VERSION 5.8 ;
BUSBITCHARS "[]" ;
DIVIDERCHAR "/" ;
UNITS
    DATABASE MICRONS 1000 ;
END UNITS

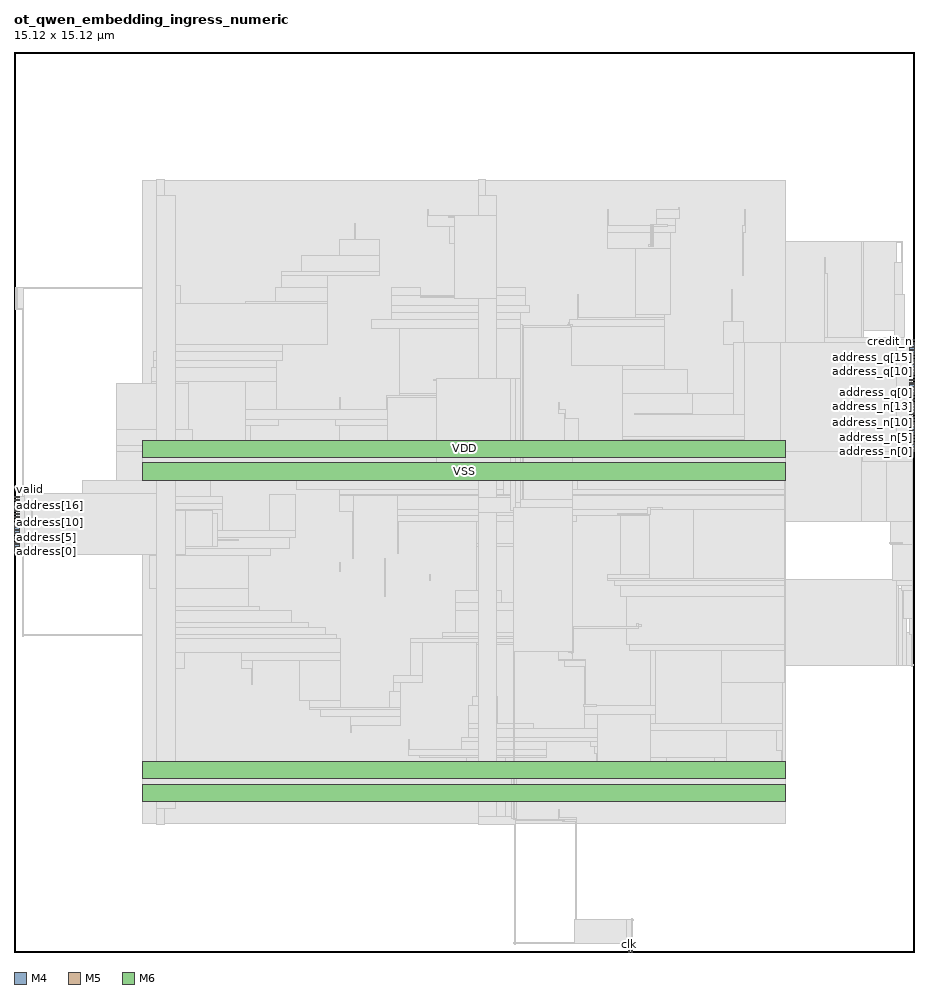
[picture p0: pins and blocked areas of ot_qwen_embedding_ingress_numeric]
MACRO ot_qwen_embedding_ingress_numeric
  FOREIGN ot_qwen_embedding_ingress_numeric 0 0 ;
  CLASS BLOCK ;
  SIZE 15.12 BY 15.12 ;
  PIN address[0]
    DIRECTION INPUT ;
    USE SIGNAL ;
    PORT
      LAYER M4 ;
        RECT  0 6.72 0.084 6.744 ;
    END
  END address[0]
  PIN address[10]
    DIRECTION INPUT ;
    USE SIGNAL ;
    PORT
      LAYER M4 ;
        RECT  0 7.2 0.084 7.224 ;
    END
  END address[10]
  PIN address[11]
    DIRECTION INPUT ;
    USE SIGNAL ;
    PORT
      LAYER M4 ;
        RECT  0 7.248 0.084 7.272 ;
    END
  END address[11]
  PIN address[12]
    DIRECTION INPUT ;
    USE SIGNAL ;
    PORT
      LAYER M4 ;
        RECT  0 7.296 0.084 7.32 ;
    END
  END address[12]
  PIN address[13]
    DIRECTION INPUT ;
    USE SIGNAL ;
    PORT
      LAYER M4 ;
        RECT  0 7.344 0.084 7.368 ;
    END
  END address[13]
  PIN address[14]
    DIRECTION INPUT ;
    USE SIGNAL ;
    PORT
      LAYER M4 ;
        RECT  0 7.392 0.084 7.416 ;
    END
  END address[14]
  PIN address[15]
    DIRECTION INPUT ;
    USE SIGNAL ;
    PORT
      LAYER M4 ;
        RECT  0 7.44 0.084 7.464 ;
    END
  END address[15]
  PIN address[16]
    DIRECTION INPUT ;
    USE SIGNAL ;
    PORT
      LAYER M4 ;
        RECT  0 7.488 0.084 7.512 ;
    END
  END address[16]
  PIN address[17]
    DIRECTION INPUT ;
    USE SIGNAL ;
    PORT
      LAYER M4 ;
        RECT  0 7.536 0.084 7.56 ;
    END
  END address[17]
  PIN address[1]
    DIRECTION INPUT ;
    USE SIGNAL ;
    PORT
      LAYER M4 ;
        RECT  0 6.768 0.084 6.792 ;
    END
  END address[1]
  PIN address[2]
    DIRECTION INPUT ;
    USE SIGNAL ;
    PORT
      LAYER M4 ;
        RECT  0 6.816 0.084 6.84 ;
    END
  END address[2]
  PIN address[3]
    DIRECTION INPUT ;
    USE SIGNAL ;
    PORT
      LAYER M4 ;
        RECT  0 6.864 0.084 6.888 ;
    END
  END address[3]
  PIN address[4]
    DIRECTION INPUT ;
    USE SIGNAL ;
    PORT
      LAYER M4 ;
        RECT  0 6.912 0.084 6.936 ;
    END
  END address[4]
  PIN address[5]
    DIRECTION INPUT ;
    USE SIGNAL ;
    PORT
      LAYER M4 ;
        RECT  0 6.96 0.084 6.984 ;
    END
  END address[5]
  PIN address[6]
    DIRECTION INPUT ;
    USE SIGNAL ;
    PORT
      LAYER M4 ;
        RECT  0 7.008 0.084 7.032 ;
    END
  END address[6]
  PIN address[7]
    DIRECTION INPUT ;
    USE SIGNAL ;
    PORT
      LAYER M4 ;
        RECT  0 7.056 0.084 7.08 ;
    END
  END address[7]
  PIN address[8]
    DIRECTION INPUT ;
    USE SIGNAL ;
    PORT
      LAYER M4 ;
        RECT  0 7.104 0.084 7.128 ;
    END
  END address[8]
  PIN address[9]
    DIRECTION INPUT ;
    USE SIGNAL ;
    PORT
      LAYER M4 ;
        RECT  0 7.152 0.084 7.176 ;
    END
  END address[9]
  PIN address_n[0]
    DIRECTION OUTPUT ;
    USE SIGNAL ;
    PORT
      LAYER M4 ;
        RECT  15.036 8.4 15.12 8.424 ;
    END
  END address_n[0]
  PIN address_n[10]
    DIRECTION OUTPUT ;
    USE SIGNAL ;
    PORT
      LAYER M4 ;
        RECT  15.036 8.88 15.12 8.904 ;
    END
  END address_n[10]
  PIN address_n[11]
    DIRECTION OUTPUT ;
    USE SIGNAL ;
    PORT
      LAYER M4 ;
        RECT  15.036 8.928 15.12 8.952 ;
    END
  END address_n[11]
  PIN address_n[12]
    DIRECTION OUTPUT ;
    USE SIGNAL ;
    PORT
      LAYER M4 ;
        RECT  15.036 8.976 15.12 9 ;
    END
  END address_n[12]
  PIN address_n[13]
    DIRECTION OUTPUT ;
    USE SIGNAL ;
    PORT
      LAYER M4 ;
        RECT  15.036 9.024 15.12 9.048 ;
    END
  END address_n[13]
  PIN address_n[14]
    DIRECTION OUTPUT ;
    USE SIGNAL ;
    PORT
      LAYER M4 ;
        RECT  15.036 9.072 15.12 9.096 ;
    END
  END address_n[14]
  PIN address_n[15]
    DIRECTION OUTPUT ;
    USE SIGNAL ;
    PORT
      LAYER M4 ;
        RECT  15.036 9.12 15.12 9.144 ;
    END
  END address_n[15]
  PIN address_n[16]
    DIRECTION OUTPUT ;
    USE SIGNAL ;
    PORT
      LAYER M4 ;
        RECT  15.036 9.168 15.12 9.192 ;
    END
  END address_n[16]
  PIN address_n[17]
    DIRECTION OUTPUT ;
    USE SIGNAL ;
    PORT
      LAYER M4 ;
        RECT  15.036 9.216 15.12 9.24 ;
    END
  END address_n[17]
  PIN address_n[1]
    DIRECTION OUTPUT ;
    USE SIGNAL ;
    PORT
      LAYER M4 ;
        RECT  15.036 8.448 15.12 8.472 ;
    END
  END address_n[1]
  PIN address_n[2]
    DIRECTION OUTPUT ;
    USE SIGNAL ;
    PORT
      LAYER M4 ;
        RECT  15.036 8.496 15.12 8.52 ;
    END
  END address_n[2]
  PIN address_n[3]
    DIRECTION OUTPUT ;
    USE SIGNAL ;
    PORT
      LAYER M4 ;
        RECT  15.036 8.544 15.12 8.568 ;
    END
  END address_n[3]
  PIN address_n[4]
    DIRECTION OUTPUT ;
    USE SIGNAL ;
    PORT
      LAYER M4 ;
        RECT  15.036 8.592 15.12 8.616 ;
    END
  END address_n[4]
  PIN address_n[5]
    DIRECTION OUTPUT ;
    USE SIGNAL ;
    PORT
      LAYER M4 ;
        RECT  15.036 8.64 15.12 8.664 ;
    END
  END address_n[5]
  PIN address_n[6]
    DIRECTION OUTPUT ;
    USE SIGNAL ;
    PORT
      LAYER M4 ;
        RECT  15.036 8.688 15.12 8.712 ;
    END
  END address_n[6]
  PIN address_n[7]
    DIRECTION OUTPUT ;
    USE SIGNAL ;
    PORT
      LAYER M4 ;
        RECT  15.036 8.736 15.12 8.76 ;
    END
  END address_n[7]
  PIN address_n[8]
    DIRECTION OUTPUT ;
    USE SIGNAL ;
    PORT
      LAYER M4 ;
        RECT  15.036 8.784 15.12 8.808 ;
    END
  END address_n[8]
  PIN address_n[9]
    DIRECTION OUTPUT ;
    USE SIGNAL ;
    PORT
      LAYER M4 ;
        RECT  15.036 8.832 15.12 8.856 ;
    END
  END address_n[9]
  PIN address_q[0]
    DIRECTION OUTPUT ;
    USE SIGNAL ;
    PORT
      LAYER M4 ;
        RECT  15.036 9.264 15.12 9.288 ;
    END
  END address_q[0]
  PIN address_q[10]
    DIRECTION OUTPUT ;
    USE SIGNAL ;
    PORT
      LAYER M4 ;
        RECT  15.036 9.744 15.12 9.768 ;
    END
  END address_q[10]
  PIN address_q[11]
    DIRECTION OUTPUT ;
    USE SIGNAL ;
    PORT
      LAYER M4 ;
        RECT  15.036 9.792 15.12 9.816 ;
    END
  END address_q[11]
  PIN address_q[12]
    DIRECTION OUTPUT ;
    USE SIGNAL ;
    PORT
      LAYER M4 ;
        RECT  15.036 9.84 15.12 9.864 ;
    END
  END address_q[12]
  PIN address_q[13]
    DIRECTION OUTPUT ;
    USE SIGNAL ;
    PORT
      LAYER M4 ;
        RECT  15.036 9.888 15.12 9.912 ;
    END
  END address_q[13]
  PIN address_q[14]
    DIRECTION OUTPUT ;
    USE SIGNAL ;
    PORT
      LAYER M4 ;
        RECT  15.036 9.936 15.12 9.96 ;
    END
  END address_q[14]
  PIN address_q[15]
    DIRECTION OUTPUT ;
    USE SIGNAL ;
    PORT
      LAYER M4 ;
        RECT  15.036 9.984 15.12 10.008 ;
    END
  END address_q[15]
  PIN address_q[16]
    DIRECTION OUTPUT ;
    USE SIGNAL ;
    PORT
      LAYER M4 ;
        RECT  15.036 10.032 15.12 10.056 ;
    END
  END address_q[16]
  PIN address_q[17]
    DIRECTION OUTPUT ;
    USE SIGNAL ;
    PORT
      LAYER M4 ;
        RECT  15.036 10.08 15.12 10.104 ;
    END
  END address_q[17]
  PIN address_q[1]
    DIRECTION OUTPUT ;
    USE SIGNAL ;
    PORT
      LAYER M4 ;
        RECT  15.036 9.312 15.12 9.336 ;
    END
  END address_q[1]
  PIN address_q[2]
    DIRECTION OUTPUT ;
    USE SIGNAL ;
    PORT
      LAYER M4 ;
        RECT  15.036 9.36 15.12 9.384 ;
    END
  END address_q[2]
  PIN address_q[3]
    DIRECTION OUTPUT ;
    USE SIGNAL ;
    PORT
      LAYER M4 ;
        RECT  15.036 9.408 15.12 9.432 ;
    END
  END address_q[3]
  PIN address_q[4]
    DIRECTION OUTPUT ;
    USE SIGNAL ;
    PORT
      LAYER M4 ;
        RECT  15.036 9.456 15.12 9.48 ;
    END
  END address_q[4]
  PIN address_q[5]
    DIRECTION OUTPUT ;
    USE SIGNAL ;
    PORT
      LAYER M4 ;
        RECT  15.036 9.504 15.12 9.528 ;
    END
  END address_q[5]
  PIN address_q[6]
    DIRECTION OUTPUT ;
    USE SIGNAL ;
    PORT
      LAYER M4 ;
        RECT  15.036 9.552 15.12 9.576 ;
    END
  END address_q[6]
  PIN address_q[7]
    DIRECTION OUTPUT ;
    USE SIGNAL ;
    PORT
      LAYER M4 ;
        RECT  15.036 9.6 15.12 9.624 ;
    END
  END address_q[7]
  PIN address_q[8]
    DIRECTION OUTPUT ;
    USE SIGNAL ;
    PORT
      LAYER M4 ;
        RECT  15.036 9.648 15.12 9.672 ;
    END
  END address_q[8]
  PIN address_q[9]
    DIRECTION OUTPUT ;
    USE SIGNAL ;
    PORT
      LAYER M4 ;
        RECT  15.036 9.696 15.12 9.72 ;
    END
  END address_q[9]
  PIN clk
    DIRECTION INPUT ;
    USE SIGNAL ;
    PORT
      LAYER M5 ;
        RECT  10.32 0 10.344 0.084 ;
    END
  END clk
  PIN credit
    DIRECTION INPUT ;
    USE SIGNAL ;
    PORT
      LAYER M4 ;
        RECT  0 7.584 0.084 7.608 ;
    END
  END credit
  PIN credit_n
    DIRECTION OUTPUT ;
    USE SIGNAL ;
    PORT
      LAYER M4 ;
        RECT  15.036 10.128 15.12 10.152 ;
    END
  END credit_n
  PIN credit_q
    DIRECTION OUTPUT ;
    USE SIGNAL ;
    PORT
      LAYER M4 ;
        RECT  15.036 10.176 15.12 10.2 ;
    END
  END credit_q
  PIN rst_n
    DIRECTION INPUT ;
    USE SIGNAL ;
    PORT
      LAYER M5 ;
        RECT  10.368 0 10.392 0.084 ;
    END
  END rst_n
  PIN valid
    DIRECTION INPUT ;
    USE SIGNAL ;
    PORT
      LAYER M4 ;
        RECT  0 7.632 0.084 7.656 ;
    END
  END valid
  PIN valid_n
    DIRECTION OUTPUT ;
    USE SIGNAL ;
    PORT
      LAYER M4 ;
        RECT  15.036 10.224 15.12 10.248 ;
    END
  END valid_n
  PIN valid_q
    DIRECTION OUTPUT ;
    USE SIGNAL ;
    PORT
      LAYER M4 ;
        RECT  15.036 10.272 15.12 10.296 ;
    END
  END valid_q
  PIN VDD
    DIRECTION INOUT ;
    USE POWER ;
    PORT
      LAYER M6 ;
        RECT  2.16 8.313 12.96 8.601 ;
        RECT  2.16 2.913 12.96 3.201 ;
    END
  END VDD
  PIN VSS
    DIRECTION INOUT ;
    USE GROUND ;
    PORT
      LAYER M6 ;
        RECT  2.16 7.929 12.96 8.217 ;
        RECT  2.16 2.529 12.96 2.817 ;
    END
  END VSS
  OBS
    LAYER RVTN ;
     RECT  2.16 2.16 12.96 2.295 ;
     RECT  2.16 2.565 12.96 2.835 ;
     RECT  2.16 3.105 12.96 3.375 ;
     RECT  2.16 3.645 12.96 3.915 ;
     RECT  2.16 4.185 12.96 4.455 ;
     RECT  2.16 4.725 12.96 4.995 ;
     RECT  2.16 5.265 12.96 5.535 ;
     RECT  2.16 5.805 12.96 6.075 ;
     RECT  2.16 6.345 12.96 6.615 ;
     RECT  2.16 6.885 12.96 7.155 ;
     RECT  2.16 7.425 12.96 7.695 ;
     RECT  2.16 7.965 12.96 8.235 ;
     RECT  2.16 8.505 12.96 8.775 ;
     RECT  2.16 9.045 12.96 9.315 ;
     RECT  2.16 9.585 12.96 9.855 ;
     RECT  2.16 10.125 12.96 10.395 ;
     RECT  2.16 10.665 12.96 10.935 ;
     RECT  2.16 11.205 12.96 11.475 ;
     RECT  2.16 11.745 12.96 12.015 ;
     RECT  2.16 12.285 12.96 12.555 ;
     RECT  2.16 12.825 12.96 12.96 ;
    LAYER RVTP ;
     RECT  2.16 2.295 12.96 2.565 ;
     RECT  2.16 2.835 12.96 3.105 ;
     RECT  2.16 3.375 12.96 3.645 ;
     RECT  2.16 3.915 12.96 4.185 ;
     RECT  2.16 4.455 12.96 4.725 ;
     RECT  2.16 4.995 12.96 5.265 ;
     RECT  2.16 5.535 12.96 5.805 ;
     RECT  2.16 6.075 12.96 6.345 ;
     RECT  2.16 6.615 12.96 6.885 ;
     RECT  2.16 7.155 12.96 7.425 ;
     RECT  2.16 7.695 12.96 7.965 ;
     RECT  2.16 8.235 12.96 8.505 ;
     RECT  2.16 8.775 12.96 9.045 ;
     RECT  2.16 9.315 12.96 9.585 ;
     RECT  2.16 9.855 12.96 10.125 ;
     RECT  2.16 10.395 12.96 10.665 ;
     RECT  2.16 10.935 12.96 11.205 ;
     RECT  2.16 11.475 12.96 11.745 ;
     RECT  2.16 12.015 12.96 12.285 ;
     RECT  2.16 12.555 12.96 12.825 ;
    LAYER M1 ;
     RECT  2.16 2.151 12.96 12.969 ;
    LAYER M2 ;
     RECT  0.031 10.791 0.167 11.16 ;
     RECT  0.139 7.326 0.175 7.344 ;
     RECT  0.175 7.128 0.211 7.344 ;
     RECT  0.211 7.128 0.347 7.38 ;
     RECT  0.347 7.326 1.147 7.38 ;
     RECT  1.723 9.522 1.759 9.54 ;
     RECT  0.139 5.31 2.16 5.328 ;
     RECT  1.147 7.326 2.16 7.92 ;
     RECT  1.759 9.252 2.16 9.54 ;
     RECT  0.167 11.142 2.16 11.16 ;
     RECT  2.16 2.151 12.96 12.969 ;
     RECT  12.96 7.236 14.243 11.934 ;
     RECT  14.243 10.098 14.279 11.934 ;
     RECT  14.243 7.236 14.675 9.342 ;
     RECT  14.675 7.776 14.783 9.342 ;
     RECT  14.279 10.44 14.819 11.934 ;
     RECT  12.96 4.806 14.827 6.264 ;
     RECT  14.755 7.011 14.827 7.029 ;
     RECT  14.827 4.806 14.855 7.029 ;
     RECT  14.783 7.938 14.855 9.342 ;
     RECT  14.819 10.44 14.855 11.034 ;
     RECT  14.855 10.476 14.891 11.034 ;
     RECT  14.855 4.806 14.927 6.102 ;
     RECT  14.855 6.858 14.927 6.948 ;
     RECT  14.819 11.916 14.927 11.934 ;
     RECT  14.927 6.858 14.963 6.876 ;
     RECT  14.855 7.938 14.963 8.649 ;
     RECT  14.891 11.016 14.963 11.034 ;
     RECT  14.927 4.806 14.999 5.904 ;
     RECT  14.963 8.514 14.999 8.649 ;
     RECT  14.999 4.806 15.071 5.364 ;
     RECT  14.999 8.514 15.071 8.604 ;
     RECT  15.071 4.806 15.107 4.824 ;
     RECT  15.071 8.514 15.107 8.532 ;
    LAYER M3 ;
     RECT  10.296 0.043 10.314 0.173 ;
     RECT  9.432 0.523 9.45 2.191 ;
     RECT  7.815 2.143 7.905 2.203 ;
     RECT  9.216 2.191 9.45 2.227 ;
     RECT  7.815 2.203 8.406 2.255 ;
     RECT  9.144 2.227 9.45 2.255 ;
     RECT  9.144 2.255 9.162 2.399 ;
     RECT  2.415 2.143 2.505 2.413 ;
     RECT  10.692 2.605 10.71 2.641 ;
     RECT  10.692 2.641 10.962 2.911 ;
     RECT  10.584 2.911 10.962 3.029 ;
     RECT  7.815 2.255 8.262 3.181 ;
     RECT  11.952 2.641 11.97 3.181 ;
     RECT  7.596 3.181 8.262 3.271 ;
     RECT  10.692 3.029 10.962 3.271 ;
     RECT  11.772 3.181 11.97 3.271 ;
     RECT  6.804 3.271 8.946 3.307 ;
     RECT  9.792 3.145 9.81 3.343 ;
     RECT  12.888 3.181 12.906 3.379 ;
     RECT  6.624 3.307 8.946 3.407 ;
     RECT  9.756 3.343 9.81 3.451 ;
     RECT  7.524 3.407 8.946 3.541 ;
     RECT  9.684 3.451 9.81 3.541 ;
     RECT  6.624 3.407 6.642 3.569 ;
     RECT  7.524 3.541 9.81 3.605 ;
     RECT  10.692 3.271 11.97 3.721 ;
     RECT  12.816 3.379 12.906 3.721 ;
     RECT  7.632 3.605 9.81 3.749 ;
     RECT  5.652 3.685 5.67 3.811 ;
     RECT  7.632 3.749 8.73 3.839 ;
     RECT  10.692 3.721 12.906 3.839 ;
     RECT  5.652 3.811 6.498 3.955 ;
     RECT  9.576 3.749 9.81 3.991 ;
     RECT  10.692 3.839 10.782 3.991 ;
     RECT  5.148 3.955 6.498 4.081 ;
     RECT  4.968 4.081 6.498 4.109 ;
     RECT  7.632 3.839 8.118 4.145 ;
     RECT  9.576 3.991 10.782 4.145 ;
     RECT  9.576 4.145 9.774 4.157 ;
     RECT  4.968 4.109 5.49 4.225 ;
     RECT  7.704 4.145 8.118 4.289 ;
     RECT  6.3 4.109 6.498 4.379 ;
     RECT  6.372 4.379 6.498 4.531 ;
     RECT  11.88 3.839 12.906 4.531 ;
     RECT  6.372 4.531 6.858 4.649 ;
     RECT  2.415 2.413 2.697 4.765 ;
     RECT  3.996 4.495 4.014 4.765 ;
     RECT  9.576 4.157 9.594 4.801 ;
     RECT  3.816 4.765 4.014 4.891 ;
     RECT  4.788 4.225 5.49 4.891 ;
     RECT  9.252 4.801 9.594 4.891 ;
     RECT  9.144 4.891 9.594 4.919 ;
     RECT  2.415 4.765 2.862 5.035 ;
     RECT  3.816 4.891 5.49 5.035 ;
     RECT  9.144 4.919 9.378 5.069 ;
     RECT  10.692 4.145 10.782 5.071 ;
     RECT  11.88 4.531 12.942 5.071 ;
     RECT  7.776 4.289 8.097 5.161 ;
     RECT  10.332 5.071 12.942 5.161 ;
     RECT  6.66 4.649 6.858 5.197 ;
     RECT  7.776 5.161 8.406 5.197 ;
     RECT  2.415 5.035 5.49 5.261 ;
     RECT  6.66 5.197 8.406 5.261 ;
     RECT  7.2 5.261 8.406 5.305 ;
     RECT  9.144 5.069 9.27 5.305 ;
     RECT  2.415 5.261 5.418 5.333 ;
     RECT  15.084 4.801 15.102 5.341 ;
     RECT  7.2 5.305 9.27 5.369 ;
     RECT  2.415 5.333 5.238 5.459 ;
     RECT  2.415 5.459 4.95 5.531 ;
     RECT  15.048 5.341 15.102 5.611 ;
     RECT  2.415 5.531 4.662 5.729 ;
     RECT  7.416 5.369 9.27 5.729 ;
     RECT  2.415 5.729 4.122 5.801 ;
     RECT  7.416 5.729 9.198 5.873 ;
     RECT  10.296 5.161 12.942 5.971 ;
     RECT  7.416 5.873 8.19 6.071 ;
     RECT  14.94 5.611 15.102 6.079 ;
     RECT  2.415 5.801 3.942 6.115 ;
     RECT  10.188 5.971 12.942 6.151 ;
     RECT  14.904 6.079 15.102 6.151 ;
     RECT  10.08 6.151 12.942 6.241 ;
     RECT  14.832 6.151 15.102 6.241 ;
     RECT  9.972 6.241 12.942 6.269 ;
     RECT  6.984 6.241 7.002 6.341 ;
     RECT  9.972 6.269 10.674 6.341 ;
     RECT  5.472 6.385 5.49 6.539 ;
     RECT  6.228 5.971 6.246 6.611 ;
     RECT  2.268 6.115 3.942 6.655 ;
     RECT  0.144 5.305 0.162 6.667 ;
     RECT  2.268 6.655 4.302 6.781 ;
     RECT  7.776 6.071 8.097 6.817 ;
     RECT  9.036 5.873 9.198 6.817 ;
     RECT  14.76 6.241 15.102 6.848 ;
     RECT  7.776 6.817 9.198 6.859 ;
     RECT  2.268 6.781 4.626 6.961 ;
     RECT  0.144 6.667 0.234 7.003 ;
     RECT  0.144 7.003 0.378 7.051 ;
     RECT  2.268 6.961 4.734 7.079 ;
     RECT  0.144 7.051 0.45 7.181 ;
     RECT  6.444 6.691 6.462 7.231 ;
     RECT  7.776 6.859 9.27 7.231 ;
     RECT  14.724 6.848 15.102 7.231 ;
     RECT  6.444 7.231 9.45 7.339 ;
     RECT  10.188 6.341 10.674 7.339 ;
     RECT  0.144 7.181 0.342 7.373 ;
     RECT  0.144 7.373 0.234 7.385 ;
     RECT  5.688 6.619 5.706 7.393 ;
     RECT  2.268 7.079 3.51 7.435 ;
     RECT  6.444 7.339 10.674 7.435 ;
     RECT  11.412 6.269 12.942 7.435 ;
     RECT  1.728 7.435 3.51 7.531 ;
     RECT  1.152 7.531 3.51 7.655 ;
     RECT  5.472 7.393 5.706 7.663 ;
     RECT  6.444 7.435 12.942 7.663 ;
     RECT  4.284 7.079 4.734 7.691 ;
     RECT  5.472 7.663 12.942 7.691 ;
     RECT  0.144 7.385 0.198 7.709 ;
     RECT  9.144 7.691 12.942 7.763 ;
     RECT  5.472 7.691 8.226 7.771 ;
     RECT  1.152 7.655 3.294 7.925 ;
     RECT  4.752 7.771 8.226 7.925 ;
     RECT  9.468 7.763 12.942 8.159 ;
     RECT  5.472 7.925 8.226 8.195 ;
     RECT  7.2 8.195 8.226 8.231 ;
     RECT  14.652 7.231 15.102 8.239 ;
     RECT  1.728 7.925 3.294 8.401 ;
     RECT  5.472 8.195 6.39 8.465 ;
     RECT  1.728 8.401 3.546 8.501 ;
     RECT  7.2 8.231 8.097 8.501 ;
     RECT  10.224 8.159 12.942 8.509 ;
     RECT  14.256 8.239 15.102 8.509 ;
     RECT  10.224 8.509 15.102 8.537 ;
     RECT  9.468 8.159 9.486 8.545 ;
     RECT  10.224 8.537 15.066 8.609 ;
     RECT  10.224 8.609 14.994 8.654 ;
     RECT  1.728 8.501 3.006 8.771 ;
     RECT  3.888 8.581 3.978 8.851 ;
     RECT  5.472 8.465 6.282 8.851 ;
     RECT  3.888 8.851 4.446 8.941 ;
     RECT  5.4 8.851 6.282 8.941 ;
     RECT  9.252 8.545 9.486 8.969 ;
     RECT  9.252 8.969 9.27 9.049 ;
     RECT  3.888 8.941 6.282 9.113 ;
     RECT  9.144 9.049 9.27 9.113 ;
     RECT  9.144 9.113 9.162 9.239 ;
     RECT  5.472 9.113 5.49 9.311 ;
     RECT  6.264 9.113 6.282 9.319 ;
     RECT  7.38 8.501 8.097 9.319 ;
     RECT  6.264 9.319 8.097 9.347 ;
     RECT  10.224 8.654 14.958 9.389 ;
     RECT  6.48 9.347 8.097 9.391 ;
     RECT  1.728 8.771 2.934 9.545 ;
     RECT  2.304 9.545 2.934 9.589 ;
     RECT  3.888 9.113 4.41 9.589 ;
     RECT  12.096 9.389 14.958 9.773 ;
     RECT  10.224 9.389 11.322 9.779 ;
     RECT  2.304 9.589 4.41 9.815 ;
     RECT  10.224 9.779 10.926 9.859 ;
     RECT  2.34 9.815 4.41 9.931 ;
     RECT  12.096 9.773 12.582 10.061 ;
     RECT  2.34 9.931 4.518 10.085 ;
     RECT  2.415 10.085 4.518 10.201 ;
     RECT  12.096 10.061 12.258 10.201 ;
     RECT  13.608 9.773 14.958 10.319 ;
     RECT  6.48 9.391 8.514 10.471 ;
     RECT  9.36 9.859 10.926 10.507 ;
     RECT  11.916 10.201 12.258 10.589 ;
     RECT  6.012 10.471 8.514 10.625 ;
     RECT  9.324 10.507 10.926 10.625 ;
     RECT  9.468 10.625 10.926 10.661 ;
     RECT  10.44 10.661 10.926 10.705 ;
     RECT  6.336 10.625 8.514 10.741 ;
     RECT  0.144 7.709 0.162 10.786 ;
     RECT  0.036 10.786 0.162 10.814 ;
     RECT  6.336 10.741 8.658 10.859 ;
     RECT  2.415 10.201 5.274 10.895 ;
     RECT  3.888 10.895 5.274 10.931 ;
     RECT  6.336 10.859 8.586 11.021 ;
     RECT  9.468 10.661 9.486 11.039 ;
     RECT  14.796 10.319 14.958 11.039 ;
     RECT  12.06 10.589 12.078 11.129 ;
     RECT  0.036 10.814 0.054 11.165 ;
     RECT  4.392 10.931 5.274 11.165 ;
     RECT  6.336 11.021 6.822 11.165 ;
     RECT  7.815 11.021 8.586 11.165 ;
     RECT  2.415 10.895 2.79 11.201 ;
     RECT  4.5 11.165 5.274 11.371 ;
     RECT  13.608 10.319 13.662 11.399 ;
     RECT  4.5 11.371 6.138 11.435 ;
     RECT  14.796 11.039 14.922 11.579 ;
     RECT  13.608 11.399 13.626 11.669 ;
     RECT  4.824 11.435 6.138 11.705 ;
     RECT  10.44 10.705 11.034 11.821 ;
     RECT  7.815 11.165 8.097 11.911 ;
     RECT  14.904 11.579 14.922 11.939 ;
     RECT  5.472 11.705 6.138 11.975 ;
     RECT  9.972 11.821 11.034 12.091 ;
     RECT  12.24 11.371 12.258 12.091 ;
     RECT  7.308 11.911 8.097 12.181 ;
     RECT  9.972 12.091 11.106 12.209 ;
     RECT  12.24 12.091 12.294 12.209 ;
     RECT  5.724 11.975 5.742 12.245 ;
     RECT  10.8 12.209 11.106 12.325 ;
     RECT  6.948 12.181 8.097 12.365 ;
     RECT  6.948 12.365 6.966 12.479 ;
     RECT  9.972 12.209 9.99 12.479 ;
     RECT  10.8 12.325 11.178 12.479 ;
     RECT  12.276 12.209 12.294 12.479 ;
     RECT  11.16 12.479 11.178 12.515 ;
     RECT  2.415 11.201 2.697 12.707 ;
     RECT  7.815 12.365 8.097 12.707 ;
     RECT  2.415 12.707 2.505 12.977 ;
     RECT  7.815 12.707 7.905 12.977 ;
    LAYER M4 ;
     RECT  0.06 6.72 0.169 7.656 ;
     RECT  0.169 6.72 0.172 7.704 ;
     RECT  0.172 6.672 2.408 7.704 ;
     RECT  2.408 2.148 2.512 12.972 ;
     RECT  2.512 2.418 2.704 12.702 ;
     RECT  2.704 6.672 2.873 7.416 ;
     RECT  2.873 6.816 3.341 7.416 ;
     RECT  3.341 6.816 3.413 7.368 ;
     RECT  3.413 6.912 3.773 6.936 ;
     RECT  7.052 9.6 7.808 9.624 ;
     RECT  6.829 10.992 7.808 11.016 ;
     RECT  7.297 12.336 7.808 12.36 ;
     RECT  7.808 2.148 7.912 12.972 ;
     RECT  7.912 2.208 8.104 12.702 ;
     RECT  8.104 7.44 8.531 7.608 ;
     RECT  9.068 5.856 9.155 5.88 ;
     RECT  8.104 2.208 9.245 2.232 ;
     RECT  9.109 6.864 9.281 6.888 ;
     RECT  9.301 10.512 9.388 10.536 ;
     RECT  9.308 5.04 9.395 5.064 ;
     RECT  8.389 0.144 9.421 0.168 ;
     RECT  9.565 4.128 9.785 4.152 ;
     RECT  9.421 0.144 10.285 0.552 ;
     RECT  10.285 0.048 10.369 0.552 ;
     RECT  10.369 0.528 10.403 0.552 ;
     RECT  10.453 5.472 10.54 5.496 ;
     RECT  10.141 7.344 10.645 7.368 ;
     RECT  10.645 7.344 10.685 7.464 ;
     RECT  10.652 11.856 10.693 11.88 ;
     RECT  10.693 11.856 10.739 12.216 ;
     RECT  10.685 7.44 10.901 7.464 ;
     RECT  10.739 12.192 10.973 12.216 ;
     RECT  10.429 9.024 11.401 9.048 ;
     RECT  11.401 9.024 12.085 9.384 ;
     RECT  12.085 9.024 12.265 10.248 ;
     RECT  12.265 8.448 12.877 10.248 ;
     RECT  12.877 8.4 14.821 10.248 ;
     RECT  14.713 6.864 14.933 6.888 ;
     RECT  14.821 8.4 15.084 10.296 ;
    LAYER M5 ;
     RECT  10.32 0.016 10.392 0.083 ;
     RECT  10.368 0.083 10.392 0.563 ;
     RECT  8.4 0.133 8.424 2.137 ;
     RECT  7.8 2.137 8.424 2.283 ;
     RECT  2.4 2.137 2.52 2.407 ;
     RECT  9.36 5.011 9.384 5.099 ;
     RECT  10.464 5.429 10.488 5.517 ;
     RECT  9.12 5.845 9.144 6.899 ;
     RECT  7.8 2.283 8.112 7.391 ;
     RECT  0.288 7.141 0.312 7.427 ;
     RECT  7.8 7.391 8.52 7.629 ;
     RECT  7.8 7.629 8.112 9.555 ;
     RECT  7.104 9.555 8.112 9.643 ;
     RECT  9.312 10.485 9.336 10.573 ;
     RECT  7.8 9.643 8.112 10.981 ;
     RECT  10.704 11.845 10.728 12.227 ;
     RECT  7.392 10.981 8.112 12.371 ;
     RECT  2.4 2.407 2.712 12.713 ;
     RECT  7.8 12.371 8.112 12.713 ;
     RECT  2.4 12.713 2.52 12.983 ;
     RECT  7.8 12.713 7.92 12.983 ;
    LAYER M6 ;
     RECT  2.16 7.929 7.093 8.601 ;
     RECT  7.093 7.929 8.341 9.632 ;
     RECT  2.16 2.529 8.366 3.201 ;
     RECT  8.341 7.424 8.427 9.632 ;
     RECT  8.366 2.24 8.435 3.201 ;
     RECT  8.427 7.552 8.501 9.632 ;
     RECT  8.501 7.552 8.555 10.528 ;
     RECT  8.555 10.496 9.347 10.528 ;
     RECT  8.555 7.552 9.387 8.601 ;
     RECT  9.333 5.056 9.406 5.472 ;
     RECT  9.406 5.44 10.499 5.472 ;
     RECT  8.435 2.529 12.96 3.201 ;
     RECT  9.387 7.929 12.96 8.601 ;
    LAYER M7 ;
     RECT  8.384 2.229 8.416 5.045 ;
     RECT  8.384 5.045 9.376 7.467 ;
     RECT  8.512 7.467 9.376 7.595 ;
     RECT  8.512 7.595 8.544 10.539 ;
  END
END ot_qwen_embedding_ingress_numeric
END LIBRARY
